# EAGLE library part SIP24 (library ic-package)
Single In Line

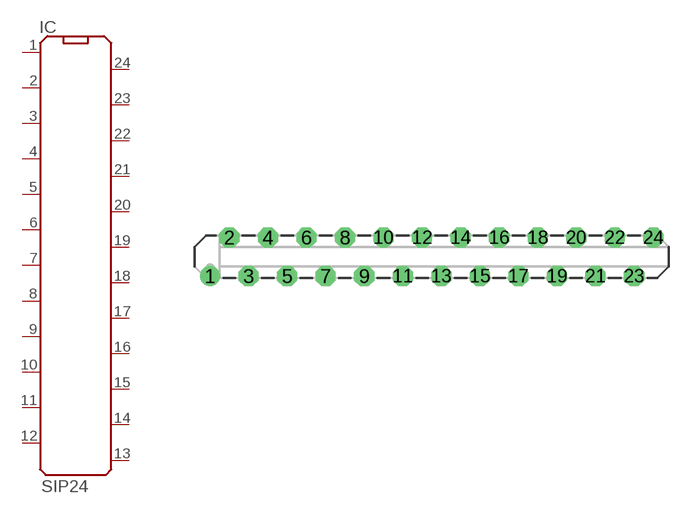
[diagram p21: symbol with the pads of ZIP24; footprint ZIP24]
Designator prefix IC

## SIP24  [ZIP24]
1  1  pas
2  2  pas
3  3  pas
4  4  pas
5  5  pas
6  6  pas
7  7  pas
8  8  pas
9  9  pas
10  10  pas
11  11  pas
12  12  pas
13  13  pas
14  14  pas
15  15  pas
16  16  pas
17  17  pas
18  18  pas
19  19  pas
20  20  pas
21  21  pas
22  22  pas
23  23  pas
24  24  pas

## Footprint ZIP24 (pad centres in mm)
Single In Line Socket
drill 0.813 round: 1 -14.605,-1.27
drill 0.813 octagon: 2 -13.335,1.27; 3 -12.065,-1.27; 4 -10.795,1.27; 5 -9.525,-1.27; 6 -8.255,1.27; 7 -6.985,-1.27; 8 -5.715,1.27; 9 -4.445,-1.27; 10 -3.175,1.27; 11 -1.905,-1.27; 12 -0.635,1.27; 13 0.635,-1.27; 14 1.905,1.27; 15 3.175,-1.27; 16 4.445,1.27; 17 5.715,-1.27; 18 6.985,1.27; 19 8.255,-1.27; 20 9.525,1.27; 21 10.795,-1.27; 22 12.065,1.27; 23 13.335,-1.27; 24 14.605,1.27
